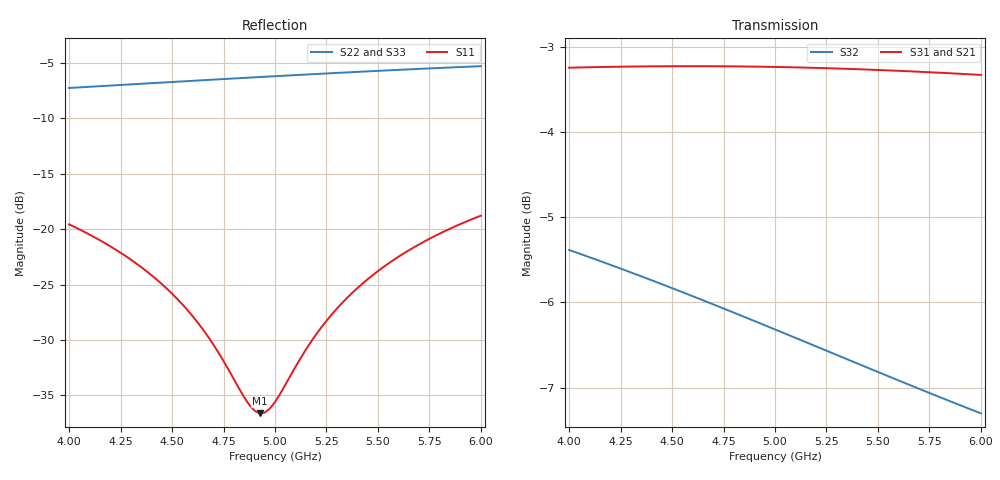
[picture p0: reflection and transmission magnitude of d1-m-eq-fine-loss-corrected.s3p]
! yapnr Order 0 prediction d1-m-eq-fine: predictions/D1/runs/d1-star/fine.s3p, loss-corrected
! substrate M-eq; coupon model OSHPARK-4L-FR408HR; correction: ratio (port line)
! |S21|, |S31| (and S12, S13) scaled, phases kept; 50 ohm, e^(+jwt)
# GHz S RI R 50
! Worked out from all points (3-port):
!   81 points, 4 GHz to 6 GHz, reference 50 ohm
!   strongest paths, dB at 4 GHz, 4.5 GHz, 5 GHz, 5.5 GHz, 6 GHz:
!     S31: -3.2, -3.2, -3.2, -3.3, -3.3
!     S21: -3.2, -3.2, -3.2, -3.3, -3.3
!     S32: -5.4, -5.8, -6.3, -6.8, -7.3
!   lowest |S11| = -36.6 dB at 4.925 GHz (marker M1), VSWR 1.03, Z = 48.6 + j0.314 ohm
!   |S11| at or under -10 dB: start of sweep to end of sweep
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4  -0.0355 0.099  -0.2263 -0.6499  -0.2263 -0.6499
   -0.2264 -0.65  0.3194 0.2942  -0.4019 -0.3577
   -0.2264 -0.65  -0.4019 -0.3577  0.3194 0.2942
4.5  -0.0151 0.0489  -0.3803 -0.5753  -0.3803 -0.5753
     -0.3804 -0.5753  0.4141 0.205  -0.461 -0.2203
     -0.3804 -0.5753  -0.461 -0.2203  0.4141 0.205
4.65  -0.0131 0.0328  -0.4224 -0.5452  -0.4224 -0.5452
      -0.4224 -0.5452  0.4379 0.1727  -0.4698 -0.1787
      -0.4224 -0.5452  -0.4698 -0.1787  0.4379 0.1727
4.875  -0.0137 0.00854  -0.4807 -0.4941  -0.4807 -0.4941
       -0.4807 -0.4941  0.4685 0.1199  -0.4759 -0.1172
       -0.4807 -0.4941  -0.4759 -0.1172  0.4685 0.1199
4.925  -0.0144 0.00323  -0.4928 -0.4818  -0.4928 -0.4818
       -0.4928 -0.4818  0.4744 0.1076  -0.4762 -0.1039
       -0.4928 -0.4818  -0.4762 -0.1039  0.4744 0.1076
5  -0.0159 -0.00466  -0.5103 -0.4629  -0.5103 -0.4629
   -0.5104 -0.4628  0.4827 0.0887  -0.4758 -0.0841
   -0.5104 -0.4628  -0.4758 -0.0841  0.4827 0.0887
5.2  -0.0224 -0.025  -0.5533 -0.4091  -0.5533 -0.4091
     -0.5533 -0.409  0.5008 0.0364  -0.4711 -0.0329
     -0.5533 -0.409  -0.4711 -0.0329  0.5008 0.0364
5.4  -0.0321 -0.0437  -0.5903 -0.3513  -0.5903 -0.3513
     -0.5903 -0.3512  0.513 -0.0182  -0.4612 0.0154
     -0.5903 -0.3512  -0.4612 0.0154  0.513 -0.0182
5.675  -0.0504 -0.0658  -0.6308 -0.2665  -0.6308 -0.2665
       -0.6308 -0.2664  0.5195 -0.0955  -0.4406 0.0764
       -0.6308 -0.2664  -0.4406 0.0764  0.5195 -0.0955
6  -0.0777 -0.085  -0.6623 -0.1611  -0.6623 -0.1611
   -0.6623 -0.161  0.5114 -0.1876  -0.4081 0.1398
   -0.6623 -0.161  -0.4081 0.1398  0.5114 -0.1876
